VERSION 5.7 ;
  NOWIREEXTENSIONATPIN ON ;
  DIVIDERCHAR "/" ;
  BUSBITCHARS "[]" ;
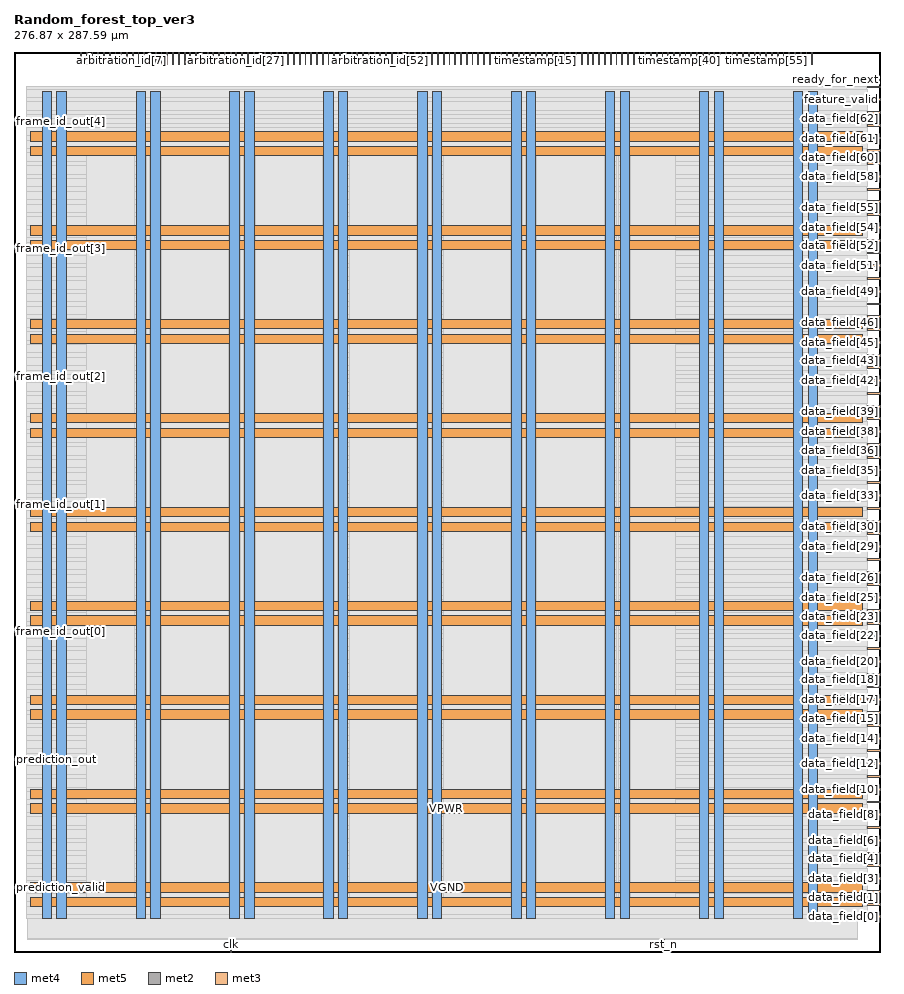
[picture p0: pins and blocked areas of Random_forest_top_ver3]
MACRO Random_forest_top_ver3
  CLASS BLOCK ;
  FOREIGN Random_forest_top_ver3 ;
  ORIGIN 0.000 0.000 ;
  SIZE 276.870 BY 287.590 ;
  PIN VGND
    DIRECTION INOUT ;
    USE GROUND ;
    PORT
      LAYER met4 ;
        RECT 13.720 10.640 16.720 274.960 ;
    END
    PORT
      LAYER met4 ;
        RECT 43.720 10.640 46.720 274.960 ;
    END
    PORT
      LAYER met4 ;
        RECT 73.720 10.640 76.720 274.960 ;
    END
    PORT
      LAYER met4 ;
        RECT 103.720 10.640 106.720 274.960 ;
    END
    PORT
      LAYER met4 ;
        RECT 133.720 10.640 136.720 274.960 ;
    END
    PORT
      LAYER met4 ;
        RECT 163.720 10.640 166.720 274.960 ;
    END
    PORT
      LAYER met4 ;
        RECT 193.720 10.640 196.720 274.960 ;
    END
    PORT
      LAYER met4 ;
        RECT 223.720 10.640 226.720 274.960 ;
    END
    PORT
      LAYER met4 ;
        RECT 253.720 10.640 256.720 274.960 ;
    END
    PORT
      LAYER met5 ;
        RECT 5.280 19.080 271.180 22.080 ;
    END
    PORT
      LAYER met5 ;
        RECT 5.280 49.080 271.180 52.080 ;
    END
    PORT
      LAYER met5 ;
        RECT 5.280 79.080 271.180 82.080 ;
    END
    PORT
      LAYER met5 ;
        RECT 5.280 109.080 271.180 112.080 ;
    END
    PORT
      LAYER met5 ;
        RECT 5.280 139.080 271.180 142.080 ;
    END
    PORT
      LAYER met5 ;
        RECT 5.280 169.080 271.180 172.080 ;
    END
    PORT
      LAYER met5 ;
        RECT 5.280 199.080 271.180 202.080 ;
    END
    PORT
      LAYER met5 ;
        RECT 5.280 229.080 271.180 232.080 ;
    END
    PORT
      LAYER met5 ;
        RECT 5.280 259.080 271.180 262.080 ;
    END
  END VGND
  PIN VPWR
    DIRECTION INOUT ;
    USE POWER ;
    PORT
      LAYER met4 ;
        RECT 9.020 10.640 12.020 274.960 ;
    END
    PORT
      LAYER met4 ;
        RECT 39.020 10.640 42.020 274.960 ;
    END
    PORT
      LAYER met4 ;
        RECT 69.020 10.640 72.020 274.960 ;
    END
    PORT
      LAYER met4 ;
        RECT 99.020 10.640 102.020 274.960 ;
    END
    PORT
      LAYER met4 ;
        RECT 129.020 10.640 132.020 274.960 ;
    END
    PORT
      LAYER met4 ;
        RECT 159.020 10.640 162.020 274.960 ;
    END
    PORT
      LAYER met4 ;
        RECT 189.020 10.640 192.020 274.960 ;
    END
    PORT
      LAYER met4 ;
        RECT 219.020 10.640 222.020 274.960 ;
    END
    PORT
      LAYER met4 ;
        RECT 249.020 10.640 252.020 274.960 ;
    END
    PORT
      LAYER met5 ;
        RECT 5.280 14.380 271.180 17.380 ;
    END
    PORT
      LAYER met5 ;
        RECT 5.280 44.380 271.180 47.380 ;
    END
    PORT
      LAYER met5 ;
        RECT 5.280 74.380 271.180 77.380 ;
    END
    PORT
      LAYER met5 ;
        RECT 5.280 104.380 271.180 107.380 ;
    END
    PORT
      LAYER met5 ;
        RECT 5.280 134.380 271.180 137.380 ;
    END
    PORT
      LAYER met5 ;
        RECT 5.280 164.380 271.180 167.380 ;
    END
    PORT
      LAYER met5 ;
        RECT 5.280 194.380 271.180 197.380 ;
    END
    PORT
      LAYER met5 ;
        RECT 5.280 224.380 271.180 227.380 ;
    END
    PORT
      LAYER met5 ;
        RECT 5.280 254.380 271.180 257.380 ;
    END
  END VPWR
  PIN arbitration_id[0]
    DIRECTION INPUT ;
    USE SIGNAL ;
    PORT
      LAYER met2 ;
        RECT 21.250 283.590 21.530 287.590 ;
    END
  END arbitration_id[0]
  PIN arbitration_id[10]
    DIRECTION INPUT ;
    USE SIGNAL ;
    PORT
      LAYER met2 ;
        RECT 39.650 283.590 39.930 287.590 ;
    END
  END arbitration_id[10]
  PIN arbitration_id[11]
    DIRECTION INPUT ;
    USE SIGNAL ;
    PORT
      LAYER met2 ;
        RECT 41.490 283.590 41.770 287.590 ;
    END
  END arbitration_id[11]
  PIN arbitration_id[12]
    DIRECTION INPUT ;
    USE SIGNAL ;
    PORT
      LAYER met2 ;
        RECT 43.330 283.590 43.610 287.590 ;
    END
  END arbitration_id[12]
  PIN arbitration_id[13]
    DIRECTION INPUT ;
    USE SIGNAL ;
    PORT
      LAYER met2 ;
        RECT 45.170 283.590 45.450 287.590 ;
    END
  END arbitration_id[13]
  PIN arbitration_id[14]
    DIRECTION INPUT ;
    USE SIGNAL ;
    PORT
      LAYER met2 ;
        RECT 47.010 283.590 47.290 287.590 ;
    END
  END arbitration_id[14]
  PIN arbitration_id[15]
    DIRECTION INPUT ;
    USE SIGNAL ;
    PORT
      LAYER met2 ;
        RECT 48.850 283.590 49.130 287.590 ;
    END
  END arbitration_id[15]
  PIN arbitration_id[16]
    DIRECTION INPUT ;
    USE SIGNAL ;
    PORT
      LAYER met2 ;
        RECT 50.690 283.590 50.970 287.590 ;
    END
  END arbitration_id[16]
  PIN arbitration_id[17]
    DIRECTION INPUT ;
    USE SIGNAL ;
    PORT
      LAYER met2 ;
        RECT 52.530 283.590 52.810 287.590 ;
    END
  END arbitration_id[17]
  PIN arbitration_id[18]
    DIRECTION INPUT ;
    USE SIGNAL ;
    PORT
      LAYER met2 ;
        RECT 54.370 283.590 54.650 287.590 ;
    END
  END arbitration_id[18]
  PIN arbitration_id[19]
    DIRECTION INPUT ;
    USE SIGNAL ;
    PORT
      LAYER met2 ;
        RECT 56.210 283.590 56.490 287.590 ;
    END
  END arbitration_id[19]
  PIN arbitration_id[1]
    DIRECTION INPUT ;
    USE SIGNAL ;
    PORT
      LAYER met2 ;
        RECT 23.090 283.590 23.370 287.590 ;
    END
  END arbitration_id[1]
  PIN arbitration_id[20]
    DIRECTION INPUT ;
    USE SIGNAL ;
    PORT
      LAYER met2 ;
        RECT 58.050 283.590 58.330 287.590 ;
    END
  END arbitration_id[20]
  PIN arbitration_id[21]
    DIRECTION INPUT ;
    USE SIGNAL ;
    PORT
      LAYER met2 ;
        RECT 59.890 283.590 60.170 287.590 ;
    END
  END arbitration_id[21]
  PIN arbitration_id[22]
    DIRECTION INPUT ;
    USE SIGNAL ;
    PORT
      LAYER met2 ;
        RECT 61.730 283.590 62.010 287.590 ;
    END
  END arbitration_id[22]
  PIN arbitration_id[23]
    DIRECTION INPUT ;
    USE SIGNAL ;
    PORT
      LAYER met2 ;
        RECT 63.570 283.590 63.850 287.590 ;
    END
  END arbitration_id[23]
  PIN arbitration_id[24]
    DIRECTION INPUT ;
    USE SIGNAL ;
    PORT
      LAYER met2 ;
        RECT 65.410 283.590 65.690 287.590 ;
    END
  END arbitration_id[24]
  PIN arbitration_id[25]
    DIRECTION INPUT ;
    USE SIGNAL ;
    PORT
      LAYER met2 ;
        RECT 67.250 283.590 67.530 287.590 ;
    END
  END arbitration_id[25]
  PIN arbitration_id[26]
    DIRECTION INPUT ;
    USE SIGNAL ;
    PORT
      LAYER met2 ;
        RECT 69.090 283.590 69.370 287.590 ;
    END
  END arbitration_id[26]
  PIN arbitration_id[27]
    DIRECTION INPUT ;
    USE SIGNAL ;
    PORT
      LAYER met2 ;
        RECT 70.930 283.590 71.210 287.590 ;
    END
  END arbitration_id[27]
  PIN arbitration_id[28]
    DIRECTION INPUT ;
    USE SIGNAL ;
    PORT
      LAYER met2 ;
        RECT 72.770 283.590 73.050 287.590 ;
    END
  END arbitration_id[28]
  PIN arbitration_id[29]
    DIRECTION INPUT ;
    USE SIGNAL ;
    PORT
      LAYER met2 ;
        RECT 74.610 283.590 74.890 287.590 ;
    END
  END arbitration_id[29]
  PIN arbitration_id[2]
    DIRECTION INPUT ;
    USE SIGNAL ;
    PORT
      LAYER met2 ;
        RECT 24.930 283.590 25.210 287.590 ;
    END
  END arbitration_id[2]
  PIN arbitration_id[30]
    DIRECTION INPUT ;
    USE SIGNAL ;
    PORT
      LAYER met2 ;
        RECT 76.450 283.590 76.730 287.590 ;
    END
  END arbitration_id[30]
  PIN arbitration_id[31]
    DIRECTION INPUT ;
    USE SIGNAL ;
    PORT
      LAYER met2 ;
        RECT 78.290 283.590 78.570 287.590 ;
    END
  END arbitration_id[31]
  PIN arbitration_id[32]
    DIRECTION INPUT ;
    USE SIGNAL ;
    PORT
      LAYER met2 ;
        RECT 80.130 283.590 80.410 287.590 ;
    END
  END arbitration_id[32]
  PIN arbitration_id[33]
    DIRECTION INPUT ;
    USE SIGNAL ;
    PORT
      LAYER met2 ;
        RECT 81.970 283.590 82.250 287.590 ;
    END
  END arbitration_id[33]
  PIN arbitration_id[34]
    DIRECTION INPUT ;
    USE SIGNAL ;
    PORT
      LAYER met2 ;
        RECT 83.810 283.590 84.090 287.590 ;
    END
  END arbitration_id[34]
  PIN arbitration_id[35]
    DIRECTION INPUT ;
    USE SIGNAL ;
    PORT
      LAYER met2 ;
        RECT 85.650 283.590 85.930 287.590 ;
    END
  END arbitration_id[35]
  PIN arbitration_id[36]
    DIRECTION INPUT ;
    USE SIGNAL ;
    PORT
      LAYER met2 ;
        RECT 87.490 283.590 87.770 287.590 ;
    END
  END arbitration_id[36]
  PIN arbitration_id[37]
    DIRECTION INPUT ;
    USE SIGNAL ;
    PORT
      LAYER met2 ;
        RECT 89.330 283.590 89.610 287.590 ;
    END
  END arbitration_id[37]
  PIN arbitration_id[38]
    DIRECTION INPUT ;
    USE SIGNAL ;
    PORT
      LAYER met2 ;
        RECT 91.170 283.590 91.450 287.590 ;
    END
  END arbitration_id[38]
  PIN arbitration_id[39]
    DIRECTION INPUT ;
    USE SIGNAL ;
    PORT
      LAYER met2 ;
        RECT 93.010 283.590 93.290 287.590 ;
    END
  END arbitration_id[39]
  PIN arbitration_id[3]
    DIRECTION INPUT ;
    USE SIGNAL ;
    PORT
      LAYER met2 ;
        RECT 26.770 283.590 27.050 287.590 ;
    END
  END arbitration_id[3]
  PIN arbitration_id[40]
    DIRECTION INPUT ;
    USE SIGNAL ;
    PORT
      LAYER met2 ;
        RECT 94.850 283.590 95.130 287.590 ;
    END
  END arbitration_id[40]
  PIN arbitration_id[41]
    DIRECTION INPUT ;
    USE SIGNAL ;
    PORT
      LAYER met2 ;
        RECT 96.690 283.590 96.970 287.590 ;
    END
  END arbitration_id[41]
  PIN arbitration_id[42]
    DIRECTION INPUT ;
    USE SIGNAL ;
    PORT
      LAYER met2 ;
        RECT 98.530 283.590 98.810 287.590 ;
    END
  END arbitration_id[42]
  PIN arbitration_id[43]
    DIRECTION INPUT ;
    USE SIGNAL ;
    PORT
      LAYER met2 ;
        RECT 100.370 283.590 100.650 287.590 ;
    END
  END arbitration_id[43]
  PIN arbitration_id[44]
    DIRECTION INPUT ;
    USE SIGNAL ;
    PORT
      LAYER met2 ;
        RECT 102.210 283.590 102.490 287.590 ;
    END
  END arbitration_id[44]
  PIN arbitration_id[45]
    DIRECTION INPUT ;
    USE SIGNAL ;
    PORT
      LAYER met2 ;
        RECT 104.050 283.590 104.330 287.590 ;
    END
  END arbitration_id[45]
  PIN arbitration_id[46]
    DIRECTION INPUT ;
    USE SIGNAL ;
    PORT
      LAYER met2 ;
        RECT 105.890 283.590 106.170 287.590 ;
    END
  END arbitration_id[46]
  PIN arbitration_id[47]
    DIRECTION INPUT ;
    USE SIGNAL ;
    PORT
      LAYER met2 ;
        RECT 107.730 283.590 108.010 287.590 ;
    END
  END arbitration_id[47]
  PIN arbitration_id[48]
    DIRECTION INPUT ;
    USE SIGNAL ;
    PORT
      LAYER met2 ;
        RECT 109.570 283.590 109.850 287.590 ;
    END
  END arbitration_id[48]
  PIN arbitration_id[49]
    DIRECTION INPUT ;
    USE SIGNAL ;
    PORT
      LAYER met2 ;
        RECT 111.410 283.590 111.690 287.590 ;
    END
  END arbitration_id[49]
  PIN arbitration_id[4]
    DIRECTION INPUT ;
    USE SIGNAL ;
    PORT
      LAYER met2 ;
        RECT 28.610 283.590 28.890 287.590 ;
    END
  END arbitration_id[4]
  PIN arbitration_id[50]
    DIRECTION INPUT ;
    USE SIGNAL ;
    PORT
      LAYER met2 ;
        RECT 113.250 283.590 113.530 287.590 ;
    END
  END arbitration_id[50]
  PIN arbitration_id[51]
    DIRECTION INPUT ;
    USE SIGNAL ;
    PORT
      LAYER met2 ;
        RECT 115.090 283.590 115.370 287.590 ;
    END
  END arbitration_id[51]
  PIN arbitration_id[52]
    DIRECTION INPUT ;
    USE SIGNAL ;
    PORT
      LAYER met2 ;
        RECT 116.930 283.590 117.210 287.590 ;
    END
  END arbitration_id[52]
  PIN arbitration_id[53]
    DIRECTION INPUT ;
    USE SIGNAL ;
    PORT
      LAYER met2 ;
        RECT 118.770 283.590 119.050 287.590 ;
    END
  END arbitration_id[53]
  PIN arbitration_id[54]
    DIRECTION INPUT ;
    USE SIGNAL ;
    PORT
      LAYER met2 ;
        RECT 120.610 283.590 120.890 287.590 ;
    END
  END arbitration_id[54]
  PIN arbitration_id[55]
    DIRECTION INPUT ;
    USE SIGNAL ;
    PORT
      LAYER met2 ;
        RECT 122.450 283.590 122.730 287.590 ;
    END
  END arbitration_id[55]
  PIN arbitration_id[56]
    DIRECTION INPUT ;
    USE SIGNAL ;
    PORT
      LAYER met2 ;
        RECT 124.290 283.590 124.570 287.590 ;
    END
  END arbitration_id[56]
  PIN arbitration_id[57]
    DIRECTION INPUT ;
    USE SIGNAL ;
    PORT
      LAYER met2 ;
        RECT 126.130 283.590 126.410 287.590 ;
    END
  END arbitration_id[57]
  PIN arbitration_id[58]
    DIRECTION INPUT ;
    USE SIGNAL ;
    PORT
      LAYER met2 ;
        RECT 127.970 283.590 128.250 287.590 ;
    END
  END arbitration_id[58]
  PIN arbitration_id[59]
    DIRECTION INPUT ;
    USE SIGNAL ;
    PORT
      LAYER met2 ;
        RECT 129.810 283.590 130.090 287.590 ;
    END
  END arbitration_id[59]
  PIN arbitration_id[5]
    DIRECTION INPUT ;
    USE SIGNAL ;
    PORT
      LAYER met2 ;
        RECT 30.450 283.590 30.730 287.590 ;
    END
  END arbitration_id[5]
  PIN arbitration_id[60]
    DIRECTION INPUT ;
    USE SIGNAL ;
    PORT
      LAYER met2 ;
        RECT 131.650 283.590 131.930 287.590 ;
    END
  END arbitration_id[60]
  PIN arbitration_id[61]
    DIRECTION INPUT ;
    USE SIGNAL ;
    PORT
      LAYER met2 ;
        RECT 133.490 283.590 133.770 287.590 ;
    END
  END arbitration_id[61]
  PIN arbitration_id[62]
    DIRECTION INPUT ;
    USE SIGNAL ;
    PORT
      LAYER met2 ;
        RECT 135.330 283.590 135.610 287.590 ;
    END
  END arbitration_id[62]
  PIN arbitration_id[63]
    DIRECTION INPUT ;
    USE SIGNAL ;
    PORT
      LAYER met2 ;
        RECT 137.170 283.590 137.450 287.590 ;
    END
  END arbitration_id[63]
  PIN arbitration_id[6]
    DIRECTION INPUT ;
    USE SIGNAL ;
    PORT
      LAYER met2 ;
        RECT 32.290 283.590 32.570 287.590 ;
    END
  END arbitration_id[6]
  PIN arbitration_id[7]
    DIRECTION INPUT ;
    USE SIGNAL ;
    PORT
      LAYER met2 ;
        RECT 34.130 283.590 34.410 287.590 ;
    END
  END arbitration_id[7]
  PIN arbitration_id[8]
    DIRECTION INPUT ;
    USE SIGNAL ;
    PORT
      LAYER met2 ;
        RECT 35.970 283.590 36.250 287.590 ;
    END
  END arbitration_id[8]
  PIN arbitration_id[9]
    DIRECTION INPUT ;
    USE SIGNAL ;
    PORT
      LAYER met2 ;
        RECT 37.810 283.590 38.090 287.590 ;
    END
  END arbitration_id[9]
  PIN clk
    DIRECTION INPUT ;
    USE SIGNAL ;
    ANTENNAGATEAREA 0.213000 ;
    ANTENNADIFFAREA 0.434700 ;
    PORT
      LAYER met2 ;
        RECT 69.090 0.000 69.370 4.000 ;
    END
  END clk
  PIN data_field[0]
    DIRECTION INPUT ;
    USE SIGNAL ;
    PORT
      LAYER met3 ;
        RECT 272.870 10.920 276.870 11.520 ;
    END
  END data_field[0]
  PIN data_field[10]
    DIRECTION INPUT ;
    USE SIGNAL ;
    PORT
      LAYER met3 ;
        RECT 272.870 51.720 276.870 52.320 ;
    END
  END data_field[10]
  PIN data_field[11]
    DIRECTION INPUT ;
    USE SIGNAL ;
    PORT
      LAYER met3 ;
        RECT 272.870 55.800 276.870 56.400 ;
    END
  END data_field[11]
  PIN data_field[12]
    DIRECTION INPUT ;
    USE SIGNAL ;
    PORT
      LAYER met3 ;
        RECT 272.870 59.880 276.870 60.480 ;
    END
  END data_field[12]
  PIN data_field[13]
    DIRECTION INPUT ;
    USE SIGNAL ;
    PORT
      LAYER met3 ;
        RECT 272.870 63.960 276.870 64.560 ;
    END
  END data_field[13]
  PIN data_field[14]
    DIRECTION INPUT ;
    USE SIGNAL ;
    PORT
      LAYER met3 ;
        RECT 272.870 68.040 276.870 68.640 ;
    END
  END data_field[14]
  PIN data_field[15]
    DIRECTION INPUT ;
    USE SIGNAL ;
    PORT
      LAYER met3 ;
        RECT 272.870 72.120 276.870 72.720 ;
    END
  END data_field[15]
  PIN data_field[16]
    DIRECTION INPUT ;
    USE SIGNAL ;
    PORT
      LAYER met3 ;
        RECT 272.870 76.200 276.870 76.800 ;
    END
  END data_field[16]
  PIN data_field[17]
    DIRECTION INPUT ;
    USE SIGNAL ;
    PORT
      LAYER met3 ;
        RECT 272.870 80.280 276.870 80.880 ;
    END
  END data_field[17]
  PIN data_field[18]
    DIRECTION INPUT ;
    USE SIGNAL ;
    PORT
      LAYER met3 ;
        RECT 272.870 84.360 276.870 84.960 ;
    END
  END data_field[18]
  PIN data_field[19]
    DIRECTION INPUT ;
    USE SIGNAL ;
    PORT
      LAYER met3 ;
        RECT 272.870 88.440 276.870 89.040 ;
    END
  END data_field[19]
  PIN data_field[1]
    DIRECTION INPUT ;
    USE SIGNAL ;
    PORT
      LAYER met3 ;
        RECT 272.870 15.000 276.870 15.600 ;
    END
  END data_field[1]
  PIN data_field[20]
    DIRECTION INPUT ;
    USE SIGNAL ;
    PORT
      LAYER met3 ;
        RECT 272.870 92.520 276.870 93.120 ;
    END
  END data_field[20]
  PIN data_field[21]
    DIRECTION INPUT ;
    USE SIGNAL ;
    PORT
      LAYER met3 ;
        RECT 272.870 96.600 276.870 97.200 ;
    END
  END data_field[21]
  PIN data_field[22]
    DIRECTION INPUT ;
    USE SIGNAL ;
    PORT
      LAYER met3 ;
        RECT 272.870 100.680 276.870 101.280 ;
    END
  END data_field[22]
  PIN data_field[23]
    DIRECTION INPUT ;
    USE SIGNAL ;
    PORT
      LAYER met3 ;
        RECT 272.870 104.760 276.870 105.360 ;
    END
  END data_field[23]
  PIN data_field[24]
    DIRECTION INPUT ;
    USE SIGNAL ;
    PORT
      LAYER met3 ;
        RECT 272.870 108.840 276.870 109.440 ;
    END
  END data_field[24]
  PIN data_field[25]
    DIRECTION INPUT ;
    USE SIGNAL ;
    PORT
      LAYER met3 ;
        RECT 272.870 112.920 276.870 113.520 ;
    END
  END data_field[25]
  PIN data_field[26]
    DIRECTION INPUT ;
    USE SIGNAL ;
    PORT
      LAYER met3 ;
        RECT 272.870 117.000 276.870 117.600 ;
    END
  END data_field[26]
  PIN data_field[27]
    DIRECTION INPUT ;
    USE SIGNAL ;
    PORT
      LAYER met3 ;
        RECT 272.870 121.080 276.870 121.680 ;
    END
  END data_field[27]
  PIN data_field[28]
    DIRECTION INPUT ;
    USE SIGNAL ;
    PORT
      LAYER met3 ;
        RECT 272.870 125.160 276.870 125.760 ;
    END
  END data_field[28]
  PIN data_field[29]
    DIRECTION INPUT ;
    USE SIGNAL ;
    PORT
      LAYER met3 ;
        RECT 272.870 129.240 276.870 129.840 ;
    END
  END data_field[29]
  PIN data_field[2]
    DIRECTION INPUT ;
    USE SIGNAL ;
    PORT
      LAYER met3 ;
        RECT 272.870 19.080 276.870 19.680 ;
    END
  END data_field[2]
  PIN data_field[30]
    DIRECTION INPUT ;
    USE SIGNAL ;
    PORT
      LAYER met3 ;
        RECT 272.870 133.320 276.870 133.920 ;
    END
  END data_field[30]
  PIN data_field[31]
    DIRECTION INPUT ;
    USE SIGNAL ;
    PORT
      LAYER met3 ;
        RECT 272.870 137.400 276.870 138.000 ;
    END
  END data_field[31]
  PIN data_field[32]
    DIRECTION INPUT ;
    USE SIGNAL ;
    PORT
      LAYER met3 ;
        RECT 272.870 141.480 276.870 142.080 ;
    END
  END data_field[32]
  PIN data_field[33]
    DIRECTION INPUT ;
    USE SIGNAL ;
    PORT
      LAYER met3 ;
        RECT 272.870 145.560 276.870 146.160 ;
    END
  END data_field[33]
  PIN data_field[34]
    DIRECTION INPUT ;
    USE SIGNAL ;
    PORT
      LAYER met3 ;
        RECT 272.870 149.640 276.870 150.240 ;
    END
  END data_field[34]
  PIN data_field[35]
    DIRECTION INPUT ;
    USE SIGNAL ;
    PORT
      LAYER met3 ;
        RECT 272.870 153.720 276.870 154.320 ;
    END
  END data_field[35]
  PIN data_field[36]
    DIRECTION INPUT ;
    USE SIGNAL ;
    PORT
      LAYER met3 ;
        RECT 272.870 157.800 276.870 158.400 ;
    END
  END data_field[36]
  PIN data_field[37]
    DIRECTION INPUT ;
    USE SIGNAL ;
    PORT
      LAYER met3 ;
        RECT 272.870 161.880 276.870 162.480 ;
    END
  END data_field[37]
  PIN data_field[38]
    DIRECTION INPUT ;
    USE SIGNAL ;
    PORT
      LAYER met3 ;
        RECT 272.870 165.960 276.870 166.560 ;
    END
  END data_field[38]
  PIN data_field[39]
    DIRECTION INPUT ;
    USE SIGNAL ;
    PORT
      LAYER met3 ;
        RECT 272.870 170.040 276.870 170.640 ;
    END
  END data_field[39]
  PIN data_field[3]
    DIRECTION INPUT ;
    USE SIGNAL ;
    PORT
      LAYER met3 ;
        RECT 272.870 23.160 276.870 23.760 ;
    END
  END data_field[3]
  PIN data_field[40]
    DIRECTION INPUT ;
    USE SIGNAL ;
    PORT
      LAYER met3 ;
        RECT 272.870 174.120 276.870 174.720 ;
    END
  END data_field[40]
  PIN data_field[41]
    DIRECTION INPUT ;
    USE SIGNAL ;
    PORT
      LAYER met3 ;
        RECT 272.870 178.200 276.870 178.800 ;
    END
  END data_field[41]
  PIN data_field[42]
    DIRECTION INPUT ;
    USE SIGNAL ;
    PORT
      LAYER met3 ;
        RECT 272.870 182.280 276.870 182.880 ;
    END
  END data_field[42]
  PIN data_field[43]
    DIRECTION INPUT ;
    USE SIGNAL ;
    PORT
      LAYER met3 ;
        RECT 272.870 186.360 276.870 186.960 ;
    END
  END data_field[43]
  PIN data_field[44]
    DIRECTION INPUT ;
    USE SIGNAL ;
    PORT
      LAYER met3 ;
        RECT 272.870 190.440 276.870 191.040 ;
    END
  END data_field[44]
  PIN data_field[45]
    DIRECTION INPUT ;
    USE SIGNAL ;
    PORT
      LAYER met3 ;
        RECT 272.870 194.520 276.870 195.120 ;
    END
  END data_field[45]
  PIN data_field[46]
    DIRECTION INPUT ;
    USE SIGNAL ;
    PORT
      LAYER met3 ;
        RECT 272.870 198.600 276.870 199.200 ;
    END
  END data_field[46]
  PIN data_field[47]
    DIRECTION INPUT ;
    USE SIGNAL ;
    PORT
      LAYER met3 ;
        RECT 272.870 202.680 276.870 203.280 ;
    END
  END data_field[47]
  PIN data_field[48]
    DIRECTION INPUT ;
    USE SIGNAL ;
    PORT
      LAYER met3 ;
        RECT 272.870 206.760 276.870 207.360 ;
    END
  END data_field[48]
  PIN data_field[49]
    DIRECTION INPUT ;
    USE SIGNAL ;
    PORT
      LAYER met3 ;
        RECT 272.870 210.840 276.870 211.440 ;
    END
  END data_field[49]
  PIN data_field[4]
    DIRECTION INPUT ;
    USE SIGNAL ;
    PORT
      LAYER met3 ;
        RECT 272.870 27.240 276.870 27.840 ;
    END
  END data_field[4]
  PIN data_field[50]
    DIRECTION INPUT ;
    USE SIGNAL ;
    PORT
      LAYER met3 ;
        RECT 272.870 214.920 276.870 215.520 ;
    END
  END data_field[50]
  PIN data_field[51]
    DIRECTION INPUT ;
    USE SIGNAL ;
    PORT
      LAYER met3 ;
        RECT 272.870 219.000 276.870 219.600 ;
    END
  END data_field[51]
  PIN data_field[52]
    DIRECTION INPUT ;
    USE SIGNAL ;
    PORT
      LAYER met3 ;
        RECT 272.870 223.080 276.870 223.680 ;
    END
  END data_field[52]
  PIN data_field[53]
    DIRECTION INPUT ;
    USE SIGNAL ;
    PORT
      LAYER met3 ;
        RECT 272.870 227.160 276.870 227.760 ;
    END
  END data_field[53]
  PIN data_field[54]
    DIRECTION INPUT ;
    USE SIGNAL ;
    PORT
      LAYER met3 ;
        RECT 272.870 231.240 276.870 231.840 ;
    END
  END data_field[54]
  PIN data_field[55]
    DIRECTION INPUT ;
    USE SIGNAL ;
    PORT
      LAYER met3 ;
        RECT 272.870 235.320 276.870 235.920 ;
    END
  END data_field[55]
  PIN data_field[56]
    DIRECTION INPUT ;
    USE SIGNAL ;
    PORT
      LAYER met3 ;
        RECT 272.870 239.400 276.870 240.000 ;
    END
  END data_field[56]
  PIN data_field[57]
    DIRECTION INPUT ;
    USE SIGNAL ;
    PORT
      LAYER met3 ;
        RECT 272.870 243.480 276.870 244.080 ;
    END
  END data_field[57]
  PIN data_field[58]
    DIRECTION INPUT ;
    USE SIGNAL ;
    PORT
      LAYER met3 ;
        RECT 272.870 247.560 276.870 248.160 ;
    END
  END data_field[58]
  PIN data_field[59]
    DIRECTION INPUT ;
    USE SIGNAL ;
    PORT
      LAYER met3 ;
        RECT 272.870 251.640 276.870 252.240 ;
    END
  END data_field[59]
  PIN data_field[5]
    DIRECTION INPUT ;
    USE SIGNAL ;
    PORT
      LAYER met3 ;
        RECT 272.870 31.320 276.870 31.920 ;
    END
  END data_field[5]
  PIN data_field[60]
    DIRECTION INPUT ;
    USE SIGNAL ;
    PORT
      LAYER met3 ;
        RECT 272.870 255.720 276.870 256.320 ;
    END
  END data_field[60]
  PIN data_field[61]
    DIRECTION INPUT ;
    USE SIGNAL ;
    PORT
      LAYER met3 ;
        RECT 272.870 259.800 276.870 260.400 ;
    END
  END data_field[61]
  PIN data_field[62]
    DIRECTION INPUT ;
    USE SIGNAL ;
    PORT
      LAYER met3 ;
        RECT 272.870 263.880 276.870 264.480 ;
    END
  END data_field[62]
  PIN data_field[63]
    DIRECTION INPUT ;
    USE SIGNAL ;
    PORT
      LAYER met3 ;
        RECT 272.870 267.960 276.870 268.560 ;
    END
  END data_field[63]
  PIN data_field[6]
    DIRECTION INPUT ;
    USE SIGNAL ;
    PORT
      LAYER met3 ;
        RECT 272.870 35.400 276.870 36.000 ;
    END
  END data_field[6]
  PIN data_field[7]
    DIRECTION INPUT ;
    USE SIGNAL ;
    PORT
      LAYER met3 ;
        RECT 272.870 39.480 276.870 40.080 ;
    END
  END data_field[7]
  PIN data_field[8]
    DIRECTION INPUT ;
    USE SIGNAL ;
    PORT
      LAYER met3 ;
        RECT 272.870 43.560 276.870 44.160 ;
    END
  END data_field[8]
  PIN data_field[9]
    DIRECTION INPUT ;
    USE SIGNAL ;
    PORT
      LAYER met3 ;
        RECT 272.870 47.640 276.870 48.240 ;
    END
  END data_field[9]
  PIN feature_valid
    DIRECTION INPUT ;
    USE SIGNAL ;
    ANTENNAGATEAREA 0.159000 ;
    ANTENNADIFFAREA 0.434700 ;
    PORT
      LAYER met3 ;
        RECT 272.870 272.040 276.870 272.640 ;
    END
  END feature_valid
  PIN frame_id_out[0]
    DIRECTION OUTPUT ;
    USE SIGNAL ;
    ANTENNADIFFAREA 1.782000 ;
    PORT
      LAYER met3 ;
        RECT 0.000 102.040 4.000 102.640 ;
    END
  END frame_id_out[0]
  PIN frame_id_out[1]
    DIRECTION OUTPUT ;
    USE SIGNAL ;
    ANTENNADIFFAREA 1.782000 ;
    PORT
      LAYER met3 ;
        RECT 0.000 142.840 4.000 143.440 ;
    END
  END frame_id_out[1]
  PIN frame_id_out[2]
    DIRECTION OUTPUT ;
    USE SIGNAL ;
    ANTENNADIFFAREA 1.782000 ;
    PORT
      LAYER met3 ;
        RECT 0.000 183.640 4.000 184.240 ;
    END
  END frame_id_out[2]
  PIN frame_id_out[3]
    DIRECTION OUTPUT ;
    USE SIGNAL ;
    ANTENNADIFFAREA 1.782000 ;
    PORT
      LAYER met3 ;
        RECT 0.000 224.440 4.000 225.040 ;
    END
  END frame_id_out[3]
  PIN frame_id_out[4]
    DIRECTION OUTPUT ;
    USE SIGNAL ;
    ANTENNADIFFAREA 1.782000 ;
    PORT
      LAYER met3 ;
        RECT 0.000 265.240 4.000 265.840 ;
    END
  END frame_id_out[4]
  PIN prediction_out
    DIRECTION OUTPUT ;
    USE SIGNAL ;
    PORT
      LAYER met3 ;
        RECT 0.000 61.240 4.000 61.840 ;
    END
  END prediction_out
  PIN prediction_valid
    DIRECTION OUTPUT ;
    USE SIGNAL ;
    ANTENNADIFFAREA 1.782000 ;
    PORT
      LAYER met3 ;
        RECT 0.000 20.440 4.000 21.040 ;
    END
  END prediction_valid
  PIN ready_for_next
    DIRECTION OUTPUT ;
    USE SIGNAL ;
    ANTENNADIFFAREA 1.782000 ;
    PORT
      LAYER met3 ;
        RECT 272.870 276.120 276.870 276.720 ;
    END
  END ready_for_next
  PIN rst_n
    DIRECTION INPUT ;
    USE SIGNAL ;
    ANTENNAGATEAREA 0.126000 ;
    ANTENNADIFFAREA 0.434700 ;
    PORT
      LAYER met2 ;
        RECT 207.550 0.000 207.830 4.000 ;
    END
  END rst_n
  PIN timestamp[0]
    DIRECTION INPUT ;
    USE SIGNAL ;
    PORT
      LAYER met2 ;
        RECT 139.010 283.590 139.290 287.590 ;
    END
  END timestamp[0]
  PIN timestamp[10]
    DIRECTION INPUT ;
    USE SIGNAL ;
    PORT
      LAYER met2 ;
        RECT 157.410 283.590 157.690 287.590 ;
    END
  END timestamp[10]
  PIN timestamp[11]
    DIRECTION INPUT ;
    USE SIGNAL ;
    PORT
      LAYER met2 ;
        RECT 159.250 283.590 159.530 287.590 ;
    END
  END timestamp[11]
  PIN timestamp[12]
    DIRECTION INPUT ;
    USE SIGNAL ;
    PORT
      LAYER met2 ;
        RECT 161.090 283.590 161.370 287.590 ;
    END
  END timestamp[12]
  PIN timestamp[13]
    DIRECTION INPUT ;
    USE SIGNAL ;
    PORT
      LAYER met2 ;
        RECT 162.930 283.590 163.210 287.590 ;
    END
  END timestamp[13]
  PIN timestamp[14]
    DIRECTION INPUT ;
    USE SIGNAL ;
    PORT
      LAYER met2 ;
        RECT 164.770 283.590 165.050 287.590 ;
    END
  END timestamp[14]
  PIN timestamp[15]
    DIRECTION INPUT ;
    USE SIGNAL ;
    PORT
      LAYER met2 ;
        RECT 166.610 283.590 166.890 287.590 ;
    END
  END timestamp[15]
  PIN timestamp[16]
    DIRECTION INPUT ;
    USE SIGNAL ;
    PORT
      LAYER met2 ;
        RECT 168.450 283.590 168.730 287.590 ;
    END
  END timestamp[16]
  PIN timestamp[17]
    DIRECTION INPUT ;
    USE SIGNAL ;
    PORT
      LAYER met2 ;
        RECT 170.290 283.590 170.570 287.590 ;
    END
  END timestamp[17]
  PIN timestamp[18]
    DIRECTION INPUT ;
    USE SIGNAL ;
    PORT
      LAYER met2 ;
        RECT 172.130 283.590 172.410 287.590 ;
    END
  END timestamp[18]
  PIN timestamp[19]
    DIRECTION INPUT ;
    USE SIGNAL ;
    PORT
      LAYER met2 ;
        RECT 173.970 283.590 174.250 287.590 ;
    END
  END timestamp[19]
  PIN timestamp[1]
    DIRECTION INPUT ;
    USE SIGNAL ;
    PORT
      LAYER met2 ;
        RECT 140.850 283.590 141.130 287.590 ;
    END
  END timestamp[1]
  PIN timestamp[20]
    DIRECTION INPUT ;
    USE SIGNAL ;
    PORT
      LAYER met2 ;
        RECT 175.810 283.590 176.090 287.590 ;
    END
  END timestamp[20]
  PIN timestamp[21]
    DIRECTION INPUT ;
    USE SIGNAL ;
    PORT
      LAYER met2 ;
        RECT 177.650 283.590 177.930 287.590 ;
    END
  END timestamp[21]
  PIN timestamp[22]
    DIRECTION INPUT ;
    USE SIGNAL ;
    PORT
      LAYER met2 ;
        RECT 179.490 283.590 179.770 287.590 ;
    END
  END timestamp[22]
  PIN timestamp[23]
    DIRECTION INPUT ;
    USE SIGNAL ;
    PORT
      LAYER met2 ;
        RECT 181.330 283.590 181.610 287.590 ;
    END
  END timestamp[23]
  PIN timestamp[24]
    DIRECTION INPUT ;
    USE SIGNAL ;
    PORT
      LAYER met2 ;
        RECT 183.170 283.590 183.450 287.590 ;
    END
  END timestamp[24]
  PIN timestamp[25]
    DIRECTION INPUT ;
    USE SIGNAL ;
    PORT
      LAYER met2 ;
        RECT 185.010 283.590 185.290 287.590 ;
    END
  END timestamp[25]
  PIN timestamp[26]
    DIRECTION INPUT ;
    USE SIGNAL ;
    PORT
      LAYER met2 ;
        RECT 186.850 283.590 187.130 287.590 ;
    END
  END timestamp[26]
  PIN timestamp[27]
    DIRECTION INPUT ;
    USE SIGNAL ;
    PORT
      LAYER met2 ;
        RECT 188.690 283.590 188.970 287.590 ;
    END
  END timestamp[27]
  PIN timestamp[28]
    DIRECTION INPUT ;
    USE SIGNAL ;
    PORT
      LAYER met2 ;
        RECT 190.530 283.590 190.810 287.590 ;
    END
  END timestamp[28]
  PIN timestamp[29]
    DIRECTION INPUT ;
    USE SIGNAL ;
    PORT
      LAYER met2 ;
        RECT 192.370 283.590 192.650 287.590 ;
    END
  END timestamp[29]
  PIN timestamp[2]
    DIRECTION INPUT ;
    USE SIGNAL ;
    PORT
      LAYER met2 ;
        RECT 142.690 283.590 142.970 287.590 ;
    END
  END timestamp[2]
  PIN timestamp[30]
    DIRECTION INPUT ;
    USE SIGNAL ;
    PORT
      LAYER met2 ;
        RECT 194.210 283.590 194.490 287.590 ;
    END
  END timestamp[30]
  PIN timestamp[31]
    DIRECTION INPUT ;
    USE SIGNAL ;
    PORT
      LAYER met2 ;
        RECT 196.050 283.590 196.330 287.590 ;
    END
  END timestamp[31]
  PIN timestamp[32]
    DIRECTION INPUT ;
    USE SIGNAL ;
    PORT
      LAYER met2 ;
        RECT 197.890 283.590 198.170 287.590 ;
    END
  END timestamp[32]
  PIN timestamp[33]
    DIRECTION INPUT ;
    USE SIGNAL ;
    PORT
      LAYER met2 ;
        RECT 199.730 283.590 200.010 287.590 ;
    END
  END timestamp[33]
  PIN timestamp[34]
    DIRECTION INPUT ;
    USE SIGNAL ;
    PORT
      LAYER met2 ;
        RECT 201.570 283.590 201.850 287.590 ;
    END
  END timestamp[34]
  PIN timestamp[35]
    DIRECTION INPUT ;
    USE SIGNAL ;
    PORT
      LAYER met2 ;
        RECT 203.410 283.590 203.690 287.590 ;
    END
  END timestamp[35]
  PIN timestamp[36]
    DIRECTION INPUT ;
    USE SIGNAL ;
    PORT
      LAYER met2 ;
        RECT 205.250 283.590 205.530 287.590 ;
    END
  END timestamp[36]
  PIN timestamp[37]
    DIRECTION INPUT ;
    USE SIGNAL ;
    PORT
      LAYER met2 ;
        RECT 207.090 283.590 207.370 287.590 ;
    END
  END timestamp[37]
  PIN timestamp[38]
    DIRECTION INPUT ;
    USE SIGNAL ;
    PORT
      LAYER met2 ;
        RECT 208.930 283.590 209.210 287.590 ;
    END
  END timestamp[38]
  PIN timestamp[39]
    DIRECTION INPUT ;
    USE SIGNAL ;
    PORT
      LAYER met2 ;
        RECT 210.770 283.590 211.050 287.590 ;
    END
  END timestamp[39]
  PIN timestamp[3]
    DIRECTION INPUT ;
    USE SIGNAL ;
    PORT
      LAYER met2 ;
        RECT 144.530 283.590 144.810 287.590 ;
    END
  END timestamp[3]
  PIN timestamp[40]
    DIRECTION INPUT ;
    USE SIGNAL ;
    PORT
      LAYER met2 ;
        RECT 212.610 283.590 212.890 287.590 ;
    END
  END timestamp[40]
  PIN timestamp[41]
    DIRECTION INPUT ;
    USE SIGNAL ;
    PORT
      LAYER met2 ;
        RECT 214.450 283.590 214.730 287.590 ;
    END
  END timestamp[41]
  PIN timestamp[42]
    DIRECTION INPUT ;
    USE SIGNAL ;
    PORT
      LAYER met2 ;
        RECT 216.290 283.590 216.570 287.590 ;
    END
  END timestamp[42]
  PIN timestamp[43]
    DIRECTION INPUT ;
    USE SIGNAL ;
    PORT
      LAYER met2 ;
        RECT 218.130 283.590 218.410 287.590 ;
    END
  END timestamp[43]
  PIN timestamp[44]
    DIRECTION INPUT ;
    USE SIGNAL ;
    PORT
      LAYER met2 ;
        RECT 219.970 283.590 220.250 287.590 ;
    END
  END timestamp[44]
  PIN timestamp[45]
    DIRECTION INPUT ;
    USE SIGNAL ;
    PORT
      LAYER met2 ;
        RECT 221.810 283.590 222.090 287.590 ;
    END
  END timestamp[45]
  PIN timestamp[46]
    DIRECTION INPUT ;
    USE SIGNAL ;
    PORT
      LAYER met2 ;
        RECT 223.650 283.590 223.930 287.590 ;
    END
  END timestamp[46]
  PIN timestamp[47]
    DIRECTION INPUT ;
    USE SIGNAL ;
    PORT
      LAYER met2 ;
        RECT 225.490 283.590 225.770 287.590 ;
    END
  END timestamp[47]
  PIN timestamp[48]
    DIRECTION INPUT ;
    USE SIGNAL ;
    PORT
      LAYER met2 ;
        RECT 227.330 283.590 227.610 287.590 ;
    END
  END timestamp[48]
  PIN timestamp[49]
    DIRECTION INPUT ;
    USE SIGNAL ;
    PORT
      LAYER met2 ;
        RECT 229.170 283.590 229.450 287.590 ;
    END
  END timestamp[49]
  PIN timestamp[4]
    DIRECTION INPUT ;
    USE SIGNAL ;
    PORT
      LAYER met2 ;
        RECT 146.370 283.590 146.650 287.590 ;
    END
  END timestamp[4]
  PIN timestamp[50]
    DIRECTION INPUT ;
    USE SIGNAL ;
    PORT
      LAYER met2 ;
        RECT 231.010 283.590 231.290 287.590 ;
    END
  END timestamp[50]
  PIN timestamp[51]
    DIRECTION INPUT ;
    USE SIGNAL ;
    PORT
      LAYER met2 ;
        RECT 232.850 283.590 233.130 287.590 ;
    END
  END timestamp[51]
  PIN timestamp[52]
    DIRECTION INPUT ;
    USE SIGNAL ;
    PORT
      LAYER met2 ;
        RECT 234.690 283.590 234.970 287.590 ;
    END
  END timestamp[52]
  PIN timestamp[53]
    DIRECTION INPUT ;
    USE SIGNAL ;
    PORT
      LAYER met2 ;
        RECT 236.530 283.590 236.810 287.590 ;
    END
  END timestamp[53]
  PIN timestamp[54]
    DIRECTION INPUT ;
    USE SIGNAL ;
    PORT
      LAYER met2 ;
        RECT 238.370 283.590 238.650 287.590 ;
    END
  END timestamp[54]
  PIN timestamp[55]
    DIRECTION INPUT ;
    USE SIGNAL ;
    PORT
      LAYER met2 ;
        RECT 240.210 283.590 240.490 287.590 ;
    END
  END timestamp[55]
  PIN timestamp[56]
    DIRECTION INPUT ;
    USE SIGNAL ;
    PORT
      LAYER met2 ;
        RECT 242.050 283.590 242.330 287.590 ;
    END
  END timestamp[56]
  PIN timestamp[57]
    DIRECTION INPUT ;
    USE SIGNAL ;
    PORT
      LAYER met2 ;
        RECT 243.890 283.590 244.170 287.590 ;
    END
  END timestamp[57]
  PIN timestamp[58]
    DIRECTION INPUT ;
    USE SIGNAL ;
    PORT
      LAYER met2 ;
        RECT 245.730 283.590 246.010 287.590 ;
    END
  END timestamp[58]
  PIN timestamp[59]
    DIRECTION INPUT ;
    USE SIGNAL ;
    PORT
      LAYER met2 ;
        RECT 247.570 283.590 247.850 287.590 ;
    END
  END timestamp[59]
  PIN timestamp[5]
    DIRECTION INPUT ;
    USE SIGNAL ;
    PORT
      LAYER met2 ;
        RECT 148.210 283.590 148.490 287.590 ;
    END
  END timestamp[5]
  PIN timestamp[60]
    DIRECTION INPUT ;
    USE SIGNAL ;
    PORT
      LAYER met2 ;
        RECT 249.410 283.590 249.690 287.590 ;
    END
  END timestamp[60]
  PIN timestamp[61]
    DIRECTION INPUT ;
    USE SIGNAL ;
    PORT
      LAYER met2 ;
        RECT 251.250 283.590 251.530 287.590 ;
    END
  END timestamp[61]
  PIN timestamp[62]
    DIRECTION INPUT ;
    USE SIGNAL ;
    PORT
      LAYER met2 ;
        RECT 253.090 283.590 253.370 287.590 ;
    END
  END timestamp[62]
  PIN timestamp[63]
    DIRECTION INPUT ;
    USE SIGNAL ;
    PORT
      LAYER met2 ;
        RECT 254.930 283.590 255.210 287.590 ;
    END
  END timestamp[63]
  PIN timestamp[6]
    DIRECTION INPUT ;
    USE SIGNAL ;
    PORT
      LAYER met2 ;
        RECT 150.050 283.590 150.330 287.590 ;
    END
  END timestamp[6]
  PIN timestamp[7]
    DIRECTION INPUT ;
    USE SIGNAL ;
    PORT
      LAYER met2 ;
        RECT 151.890 283.590 152.170 287.590 ;
    END
  END timestamp[7]
  PIN timestamp[8]
    DIRECTION INPUT ;
    USE SIGNAL ;
    PORT
      LAYER met2 ;
        RECT 153.730 283.590 154.010 287.590 ;
    END
  END timestamp[8]
  PIN timestamp[9]
    DIRECTION INPUT ;
    USE SIGNAL ;
    PORT
      LAYER met2 ;
        RECT 155.570 283.590 155.850 287.590 ;
    END
  END timestamp[9]
  OBS
      LAYER nwell ;
        RECT 5.330 10.795 271.130 274.910 ;
      LAYER li1 ;
        RECT 5.520 10.795 270.940 274.805 ;
      LAYER met1 ;
        RECT 4.210 10.640 270.940 274.960 ;
      LAYER met2 ;
        RECT 4.230 4.280 269.470 276.605 ;
        RECT 4.230 4.000 68.810 4.280 ;
        RECT 69.650 4.000 207.270 4.280 ;
        RECT 208.110 4.000 269.470 4.280 ;
      LAYER met3 ;
        RECT 3.990 275.720 272.470 276.585 ;
        RECT 3.990 273.040 272.870 275.720 ;
        RECT 3.990 271.640 272.470 273.040 ;
        RECT 3.990 268.960 272.870 271.640 ;
        RECT 3.990 267.560 272.470 268.960 ;
        RECT 3.990 266.240 272.870 267.560 ;
        RECT 4.400 264.880 272.870 266.240 ;
        RECT 4.400 264.840 272.470 264.880 ;
        RECT 3.990 263.480 272.470 264.840 ;
        RECT 3.990 260.800 272.870 263.480 ;
        RECT 3.990 259.400 272.470 260.800 ;
        RECT 3.990 256.720 272.870 259.400 ;
        RECT 3.990 255.320 272.470 256.720 ;
        RECT 3.990 252.640 272.870 255.320 ;
        RECT 3.990 251.240 272.470 252.640 ;
        RECT 3.990 248.560 272.870 251.240 ;
        RECT 3.990 247.160 272.470 248.560 ;
        RECT 3.990 244.480 272.870 247.160 ;
        RECT 3.990 243.080 272.470 244.480 ;
        RECT 3.990 240.400 272.870 243.080 ;
        RECT 3.990 239.000 272.470 240.400 ;
        RECT 3.990 236.320 272.870 239.000 ;
        RECT 3.990 234.920 272.470 236.320 ;
        RECT 3.990 232.240 272.870 234.920 ;
        RECT 3.990 230.840 272.470 232.240 ;
        RECT 3.990 228.160 272.870 230.840 ;
        RECT 3.990 226.760 272.470 228.160 ;
        RECT 3.990 225.440 272.870 226.760 ;
        RECT 4.400 224.080 272.870 225.440 ;
        RECT 4.400 224.040 272.470 224.080 ;
        RECT 3.990 222.680 272.470 224.040 ;
        RECT 3.990 220.000 272.870 222.680 ;
        RECT 3.990 218.600 272.470 220.000 ;
        RECT 3.990 215.920 272.870 218.600 ;
        RECT 3.990 214.520 272.470 215.920 ;
        RECT 3.990 211.840 272.870 214.520 ;
        RECT 3.990 210.440 272.470 211.840 ;
        RECT 3.990 207.760 272.870 210.440 ;
        RECT 3.990 206.360 272.470 207.760 ;
        RECT 3.990 203.680 272.870 206.360 ;
        RECT 3.990 202.280 272.470 203.680 ;
        RECT 3.990 199.600 272.870 202.280 ;
        RECT 3.990 198.200 272.470 199.600 ;
        RECT 3.990 195.520 272.870 198.200 ;
        RECT 3.990 194.120 272.470 195.520 ;
        RECT 3.990 191.440 272.870 194.120 ;
        RECT 3.990 190.040 272.470 191.440 ;
        RECT 3.990 187.360 272.870 190.040 ;
        RECT 3.990 185.960 272.470 187.360 ;
        RECT 3.990 184.640 272.870 185.960 ;
        RECT 4.400 183.280 272.870 184.640 ;
        RECT 4.400 183.240 272.470 183.280 ;
        RECT 3.990 181.880 272.470 183.240 ;
        RECT 3.990 179.200 272.870 181.880 ;
        RECT 3.990 177.800 272.470 179.200 ;
        RECT 3.990 175.120 272.870 177.800 ;
        RECT 3.990 173.720 272.470 175.120 ;
        RECT 3.990 171.040 272.870 173.720 ;
        RECT 3.990 169.640 272.470 171.040 ;
        RECT 3.990 166.960 272.870 169.640 ;
        RECT 3.990 165.560 272.470 166.960 ;
        RECT 3.990 162.880 272.870 165.560 ;
        RECT 3.990 161.480 272.470 162.880 ;
        RECT 3.990 158.800 272.870 161.480 ;
        RECT 3.990 157.400 272.470 158.800 ;
        RECT 3.990 154.720 272.870 157.400 ;
        RECT 3.990 153.320 272.470 154.720 ;
        RECT 3.990 150.640 272.870 153.320 ;
        RECT 3.990 149.240 272.470 150.640 ;
        RECT 3.990 146.560 272.870 149.240 ;
        RECT 3.990 145.160 272.470 146.560 ;
        RECT 3.990 143.840 272.870 145.160 ;
        RECT 4.400 142.480 272.870 143.840 ;
        RECT 4.400 142.440 272.470 142.480 ;
        RECT 3.990 141.080 272.470 142.440 ;
        RECT 3.990 138.400 272.870 141.080 ;
        RECT 3.990 137.000 272.470 138.400 ;
        RECT 3.990 134.320 272.870 137.000 ;
        RECT 3.990 132.920 272.470 134.320 ;
        RECT 3.990 130.240 272.870 132.920 ;
        RECT 3.990 128.840 272.470 130.240 ;
        RECT 3.990 126.160 272.870 128.840 ;
        RECT 3.990 124.760 272.470 126.160 ;
        RECT 3.990 122.080 272.870 124.760 ;
        RECT 3.990 120.680 272.470 122.080 ;
        RECT 3.990 118.000 272.870 120.680 ;
        RECT 3.990 116.600 272.470 118.000 ;
        RECT 3.990 113.920 272.870 116.600 ;
        RECT 3.990 112.520 272.470 113.920 ;
        RECT 3.990 109.840 272.870 112.520 ;
        RECT 3.990 108.440 272.470 109.840 ;
        RECT 3.990 105.760 272.870 108.440 ;
        RECT 3.990 104.360 272.470 105.760 ;
        RECT 3.990 103.040 272.870 104.360 ;
        RECT 4.400 101.680 272.870 103.040 ;
        RECT 4.400 101.640 272.470 101.680 ;
        RECT 3.990 100.280 272.470 101.640 ;
        RECT 3.990 97.600 272.870 100.280 ;
        RECT 3.990 96.200 272.470 97.600 ;
        RECT 3.990 93.520 272.870 96.200 ;
        RECT 3.990 92.120 272.470 93.520 ;
        RECT 3.990 89.440 272.870 92.120 ;
        RECT 3.990 88.040 272.470 89.440 ;
        RECT 3.990 85.360 272.870 88.040 ;
        RECT 3.990 83.960 272.470 85.360 ;
        RECT 3.990 81.280 272.870 83.960 ;
        RECT 3.990 79.880 272.470 81.280 ;
        RECT 3.990 77.200 272.870 79.880 ;
        RECT 3.990 75.800 272.470 77.200 ;
        RECT 3.990 73.120 272.870 75.800 ;
        RECT 3.990 71.720 272.470 73.120 ;
        RECT 3.990 69.040 272.870 71.720 ;
        RECT 3.990 67.640 272.470 69.040 ;
        RECT 3.990 64.960 272.870 67.640 ;
        RECT 3.990 63.560 272.470 64.960 ;
        RECT 3.990 62.240 272.870 63.560 ;
        RECT 4.400 60.880 272.870 62.240 ;
        RECT 4.400 60.840 272.470 60.880 ;
        RECT 3.990 59.480 272.470 60.840 ;
        RECT 3.990 56.800 272.870 59.480 ;
        RECT 3.990 55.400 272.470 56.800 ;
        RECT 3.990 52.720 272.870 55.400 ;
        RECT 3.990 51.320 272.470 52.720 ;
        RECT 3.990 48.640 272.870 51.320 ;
        RECT 3.990 47.240 272.470 48.640 ;
        RECT 3.990 44.560 272.870 47.240 ;
        RECT 3.990 43.160 272.470 44.560 ;
        RECT 3.990 40.480 272.870 43.160 ;
        RECT 3.990 39.080 272.470 40.480 ;
        RECT 3.990 36.400 272.870 39.080 ;
        RECT 3.990 35.000 272.470 36.400 ;
        RECT 3.990 32.320 272.870 35.000 ;
        RECT 3.990 30.920 272.470 32.320 ;
        RECT 3.990 28.240 272.870 30.920 ;
        RECT 3.990 26.840 272.470 28.240 ;
        RECT 3.990 24.160 272.870 26.840 ;
        RECT 3.990 22.760 272.470 24.160 ;
        RECT 3.990 21.440 272.870 22.760 ;
        RECT 4.400 20.080 272.870 21.440 ;
        RECT 4.400 20.040 272.470 20.080 ;
        RECT 3.990 18.680 272.470 20.040 ;
        RECT 3.990 16.000 272.870 18.680 ;
        RECT 3.990 14.600 272.470 16.000 ;
        RECT 3.990 11.920 272.870 14.600 ;
        RECT 3.990 10.715 272.470 11.920 ;
      LAYER met4 ;
        RECT 23.295 17.175 38.620 256.185 ;
        RECT 42.420 17.175 43.320 256.185 ;
        RECT 47.120 17.175 68.620 256.185 ;
        RECT 72.420 17.175 73.320 256.185 ;
        RECT 77.120 17.175 98.620 256.185 ;
        RECT 102.420 17.175 103.320 256.185 ;
        RECT 107.120 17.175 128.620 256.185 ;
        RECT 132.420 17.175 133.320 256.185 ;
        RECT 137.120 17.175 158.620 256.185 ;
        RECT 162.420 17.175 163.320 256.185 ;
        RECT 167.120 17.175 188.620 256.185 ;
        RECT 192.420 17.175 193.320 256.185 ;
        RECT 197.120 17.175 211.305 256.185 ;
  END
END Random_forest_top_ver3
END LIBRARY

